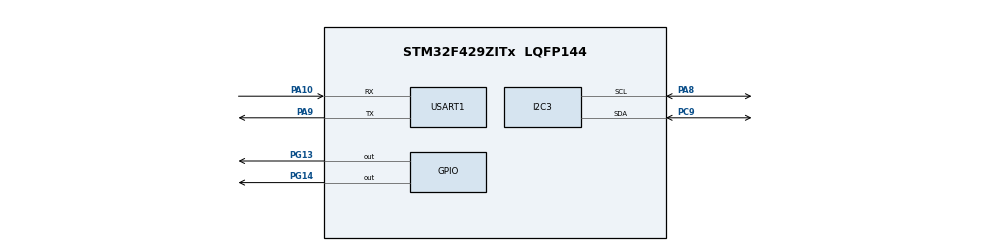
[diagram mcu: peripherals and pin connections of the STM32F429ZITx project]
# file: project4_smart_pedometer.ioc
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FREERTOS.Mutexes01=myMutex01,Dynamic,NULL,Available
FREERTOS.Queues01=myQueue01,16,uint16_t,0,Dynamic,NULL,NULL
FREERTOS.Tasks01=defaultTask,0,128,StartDefaultTask,Default,NULL,Dynamic,NULL,NULL
FREERTOS.configUSE_NEWLIB_REENTRANT=1
FREERTOS.configUSE_TIMERS=1
Mcu.Family=STM32F4
Mcu.Name=STM32F429ZITx
Mcu.Package=LQFP144
NVIC.PriorityGroup=NVIC_PRIORITYGROUP_4
NVIC.TIM1_UP_TIM10_IRQn=true\:15\:0\:false\:false\:true\:false\:false\:true\:true
NVIC.TimeBase=TIM1_UP_TIM10_IRQn
NVIC.TimeBaseIP=TIM1
NVIC.USART1_IRQn=true\:5\:0\:false\:false\:true\:true\:true\:true\:true
PA10.Mode=Asynchronous
PA10.Signal=USART1_RX
PA8.Mode=I2C
PA8.Signal=I2C3_SCL
PA9.Mode=Asynchronous
PA9.Signal=USART1_TX
PC9.Mode=I2C
PC9.Signal=I2C3_SDA
PG13.Signal=GPIO_Output
PG14.Signal=GPIO_Output
ProjectManager.HeapSize=0x200
ProjectManager.StackSize=0x400
ProjectManager.TargetToolchain=STM32CubeIDE
RCC.48MHZClocksFreq_Value=90000000
RCC.AHBFreq_Value=180000000
RCC.APB1CLKDivider=RCC_HCLK_DIV4
RCC.APB1Freq_Value=45000000
RCC.APB1TimFreq_Value=90000000
RCC.APB2CLKDivider=RCC_HCLK_DIV2
RCC.APB2Freq_Value=90000000
RCC.APB2TimFreq_Value=180000000
RCC.CortexFreq_Value=180000000
RCC.HCLKFreq_Value=180000000
RCC.HSE_VALUE=25000000
RCC.HSI_VALUE=16000000
RCC.LSE_VALUE=32768
RCC.PLLM=8
RCC.PLLN=180
RCC.SYSCLKFreq_VALUE=180000000
RCC.SYSCLKSource=RCC_SYSCLKSOURCE_PLLCLK
RCC.VCOOutputFreq_Value=360000000
USART1.VirtualMode=VM_ASYNC
VP_FREERTOS_VS_CMSIS_V1.Mode=CMSIS_V1
VP_SYS_VS_tim1.Mode=TIM1
board=custom

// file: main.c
/* USER CODE BEGIN Header */
/**
  ******************************************************************************
  * @file           : main.c
  * @brief          : Main program body
  ******************************************************************************
  * @attention
  *
  * Copyright (c) 2026 STMicroelectronics.
  * All rights reserved.
  *
  * This software is licensed under terms that can be found in the LICENSE file
  * in the root directory of this software component.
  * If no LICENSE file comes with this software, it is provided AS-IS.
  *
  ******************************************************************************
  */
/* USER CODE END Header */
#include "main.h"
#include "cmsis_os.h"

/* USER CODE BEGIN Includes */
#include <stdio.h>

/* USER CODE END Includes */

/* USER CODE BEGIN PTD */
#include <stdio.h>
#include <string.h>
#include <math.h>

void MPU6050_Init(void);
void MPU6050_Read(void);
#define MPU6050_ADDR (0x68 << 1)
uint8_t data[14];
uint16_t g_Ax, g_Ay, g_Az, g_Gx, g_Gy, g_Gz;
char uart_buf[100];

TaskHandle_t sensortaskHandle,pedometertaskhandle,displayhandle;
QueueHandle_t alertQueue;
/* USER CODE END PTD */

I2C_HandleTypeDef hi2c3;

UART_HandleTypeDef huart1;

osThreadId defaultTaskHandle;
osThreadId myTask02Handle;
osTimerId myTimer01Handle;
osMutexId myMutex01Handle;

void SystemClock_Config(void);
static void MX_GPIO_Init(void);
static void MX_I2C3_Init(void);
static void MX_USART1_UART_Init(void);
//void StartDefaultTask(void const * argument);
void StartTask02(void const * argument);
void Callback01(void const * argument);

/* USER CODE BEGIN 0 */
void MPU6050_Init(void)
{
  uint8_t check;
  uint8_t data;

  // Check WHO_AM_I
  HAL_I2C_Mem_Read(&hi2c3, MPU6050_ADDR, 0x75, 1, &check, 1, HAL_MAX_DELAY);

  // Wake up MPU6050
  data = 0;
  HAL_I2C_Mem_Write(&hi2c3, MPU6050_ADDR, 0x6B, 1, &data, 1, HAL_MAX_DELAY);

  // Set accel ±2g
  data = 0x00;
  HAL_I2C_Mem_Write(&hi2c3, MPU6050_ADDR, 0x1C, 1, &data, 1, HAL_MAX_DELAY);

  // Set gyro ±250 dps
  data = 0x00;
  HAL_I2C_Mem_Write(&hi2c3, MPU6050_ADDR, 0x1B, 1, &data, 1, HAL_MAX_DELAY);
}
void MPU6050_Read(void)
{
  HAL_I2C_Mem_Read(&hi2c3, MPU6050_ADDR, 0x3B, 1, data, 14, HAL_MAX_DELAY);

  g_Ax = (int16_t)(data[0] << 8 | data[1]);
  g_Ay = (int16_t)(data[2] << 8 | data[3]);
  g_Az = (int16_t)(data[4] << 8 | data[5]);

  g_Gx = (int16_t)(data[8] << 8 | data[9]);
  g_Gy = (int16_t)(data[10] << 8 | data[11]);
  g_Gz = (int16_t)(data[12] << 8 | data[13]);
}

void SensorTask(void*arg);
void Pedometertask(void*arg);
void Displaytask(void*arg);
/* USER CODE END 0 */

int main(void)
{

  /* MCU Configuration--------------------------------------------------------*/

  /* Reset of all peripherals, Initializes the Flash interface and the Systick. */
  HAL_Init();

  /* Configure the system clock */
  SystemClock_Config();

  /* Initialize all configured peripherals */
  MX_GPIO_Init();
  MX_I2C3_Init();
  MX_USART1_UART_Init();
  /* USER CODE BEGIN 2 */
  MPU6050_Init(); //imp

  // queue to send the data form pedometer to the alert task
  alertQueue = xQueueCreate(5,sizeof(int));

  TaskHandle_t sensortaskHandle,pedometertaskhandle,displayhandle;

  xTaskCreate(SensorTask,"Sensor",128, NULL, 1,&sensortaskHandle);
  xTaskCreate(Pedometertask,"Pedometer",128, NULL, 2,&pedometertaskhandle);
  xTaskCreate(Displaytask,"Display",256, NULL,1,&displayhandle);

  vTaskStartScheduler(); // oskernal start

  /* USER CODE END 2 */

  /* Create the mutex(es) */
  /* definition and creation of myMutex01 */
//  osMutexDef(myMutex01);
//  myMutex01Handle = osMutexCreate(osMutex(myMutex01));

  /* Create the timer(s) */
  /* definition and creation of myTimer01 */
//  osTimerDef(myTimer01, Callback01);
//  myTimer01Handle = osTimerCreate(osTimer(myTimer01), osTimerPeriodic, NULL);

  /* Create the thread(s) */
  /* definition and creation of defaultTask */
//  osThreadDef(defaultTask, StartDefaultTask, osPriorityNormal, 0, 128);
//  defaultTaskHandle = osThreadCreate(osThread(defaultTask), NULL);

  /* definition and creation of myTask02 */
//  osThreadDef(myTask02, StartTask02, osPriorityIdle, 0, 128);
//  myTask02Handle = osThreadCreate(osThread(myTask02), NULL);

  /* Start scheduler */
  //osKernelStart();

  /* We should never get here as control is now taken by the scheduler */

  /* Infinite loop */
  while (1)
  {

  }
}

void SystemClock_Config(void)
{
  RCC_OscInitTypeDef RCC_OscInitStruct = {0};
  RCC_ClkInitTypeDef RCC_ClkInitStruct = {0};

  /** Configure the main internal regulator output voltage
  */
  __HAL_RCC_PWR_CLK_ENABLE();
  __HAL_PWR_VOLTAGESCALING_CONFIG(PWR_REGULATOR_VOLTAGE_SCALE3);

  /** Initializes the RCC Oscillators according to the specified parameters
  * in the RCC_OscInitTypeDef structure.
  */
  RCC_OscInitStruct.OscillatorType = RCC_OSCILLATORTYPE_HSI;
  RCC_OscInitStruct.HSIState = RCC_HSI_ON;
  RCC_OscInitStruct.HSICalibrationValue = RCC_HSICALIBRATION_DEFAULT;
  RCC_OscInitStruct.PLL.PLLState = RCC_PLL_NONE;
  if (HAL_RCC_OscConfig(&RCC_OscInitStruct) != HAL_OK)
  {
    Error_Handler();
  }

  /** Initializes the CPU, AHB and APB buses clocks
  */
  RCC_ClkInitStruct.ClockType = RCC_CLOCKTYPE_HCLK|RCC_CLOCKTYPE_SYSCLK
                              |RCC_CLOCKTYPE_PCLK1|RCC_CLOCKTYPE_PCLK2;
  RCC_ClkInitStruct.SYSCLKSource = RCC_SYSCLKSOURCE_HSI;
  RCC_ClkInitStruct.AHBCLKDivider = RCC_SYSCLK_DIV1;
  RCC_ClkInitStruct.APB1CLKDivider = RCC_HCLK_DIV1;
  RCC_ClkInitStruct.APB2CLKDivider = RCC_HCLK_DIV1;

  if (HAL_RCC_ClockConfig(&RCC_ClkInitStruct, FLASH_LATENCY_0) != HAL_OK)
  {
    Error_Handler();
  }
}

static void MX_I2C3_Init(void)
{

  hi2c3.Instance = I2C3;
  hi2c3.Init.ClockSpeed = 100000;
  hi2c3.Init.DutyCycle = I2C_DUTYCYCLE_2;
  hi2c3.Init.OwnAddress1 = 0;
  hi2c3.Init.AddressingMode = I2C_ADDRESSINGMODE_7BIT;
  hi2c3.Init.DualAddressMode = I2C_DUALADDRESS_DISABLE;
  hi2c3.Init.OwnAddress2 = 0;
  hi2c3.Init.GeneralCallMode = I2C_GENERALCALL_DISABLE;
  hi2c3.Init.NoStretchMode = I2C_NOSTRETCH_DISABLE;
  if (HAL_I2C_Init(&hi2c3) != HAL_OK)
  {
    Error_Handler();
  }

  /** Configure Analogue filter
  */
  if (HAL_I2CEx_ConfigAnalogFilter(&hi2c3, I2C_ANALOGFILTER_ENABLE) != HAL_OK)
  {
    Error_Handler();
  }

  /** Configure Digital filter
  */
  if (HAL_I2CEx_ConfigDigitalFilter(&hi2c3, 0) != HAL_OK)
  {
    Error_Handler();
  }

}

static void MX_USART1_UART_Init(void)
{

  huart1.Instance = USART1;
  huart1.Init.BaudRate = 115200;
  huart1.Init.WordLength = UART_WORDLENGTH_8B;
  huart1.Init.StopBits = UART_STOPBITS_1;
  huart1.Init.Parity = UART_PARITY_NONE;
  huart1.Init.Mode = UART_MODE_TX_RX;
  huart1.Init.HwFlowCtl = UART_HWCONTROL_NONE;
  huart1.Init.OverSampling = UART_OVERSAMPLING_16;
  if (HAL_UART_Init(&huart1) != HAL_OK)
  {
    Error_Handler();
  }

}

static void MX_GPIO_Init(void)
{
  GPIO_InitTypeDef GPIO_InitStruct = {0};

  /* GPIO Ports Clock Enable */
  __HAL_RCC_GPIOC_CLK_ENABLE();
  __HAL_RCC_GPIOA_CLK_ENABLE();
  __HAL_RCC_GPIOG_CLK_ENABLE();

  /*Configure GPIO pin Output Level */
  HAL_GPIO_WritePin(GPIOG, GPIO_PIN_13|GPIO_PIN_14, GPIO_PIN_RESET);

  /*Configure GPIO pins : PG13 PG14 */
  GPIO_InitStruct.Pin = GPIO_PIN_13|GPIO_PIN_14;
  GPIO_InitStruct.Mode = GPIO_MODE_OUTPUT_PP;
  GPIO_InitStruct.Pull = GPIO_NOPULL;
  GPIO_InitStruct.Speed = GPIO_SPEED_FREQ_LOW;
  HAL_GPIO_Init(GPIOG, &GPIO_InitStruct);

}

/* USER CODE BEGIN 4 */

//PedometerTask
//      │
//      │  xQueueSend(alertQueue, &step_count)
//      ▼
//Queue
//      ▼
//DisplayTask
//      │
//      │ xQueueReceive()
//      ▼
//Print steps to UART

void SensorTask(void *arg)
{
	for(;;)
	{
		MPU6050_Read();  // read the sensor

//		sprintf(uart_buf, "Ax=%d Ay=%d Az=%d | Gx=%d Gy=%d Gz=%d\r\n", g_Ax, g_Ay, g_Az, g_Gx, g_Gy, g_Gz);
//
//		HAL_UART_Transmit(&huart1, (uint8_t*)uart_buf, strlen(uart_buf), portMAX_DELAY);

		HAL_GPIO_TogglePin(GPIOG, GPIO_PIN_13);  // sending the sensor task

		vTaskDelay(pdMS_TO_TICKS(20));
	}
}
void Pedometertask(void*arg)
{
	int step_count = 0;
	float prev_magnitude = 0.0f;
	float magnitude;
	while(1)
	{
		// TODO: Calculate acceleration magnitude
		magnitude = sqrt(g_Ax*g_Ax +g_Ay*g_Ay +g_Az*g_Az);

		// TODO: Calculate swing speed from gyroscope
		float gyro_dps = g_Gy / 131.0;

		// TODO: Implement the step detection logic (Threshold + Edge + Swing)
		if(magnitude > 18000 && prev_magnitude < 18000 &&fabs(gyro_dps) > 15)
		{
			step_count++;

			// TODO: If step detected, send to queue and apply cooldown delay

			xQueueSend(alertQueue, &step_count, 0);

			vTaskDelay(pdMS_TO_TICKS(250));
		}

		// TODO: Update prev_magnitude
		prev_magnitude = magnitude;
		vTaskDelay(pdMS_TO_TICKS(20));
	}
}

void Displaytask(void*arg)
{
	int steps;
	uint16_t uart_buf[50];
	for(;;)
	{
			xQueueReceive(alertQueue,&steps,portMAX_DELAY);

			sprintf(uart_buf,"Steps: %d\r\n",steps);

			HAL_UART_Transmit(&huart1,(uint8_t*)uart_buf,strlen(uart_buf),HAL_MAX_DELAY);
	}
}
/* USER CODE END 4 */

void StartDefaultTask(void const * argument)
{
  /* USER CODE BEGIN 5 */
//  /* Infinite loop */
//  for(;;)
//  {
//    osDelay(1);
//  }
  /* USER CODE END 5 */
}

void StartTask02(void const * argument)
{
  /* USER CODE BEGIN StartTask02 */
//  /* Infinite loop */
//  for(;;)
//  {
//    osDelay(1);
//  }
  /* USER CODE END StartTask02 */
}

/* Callback01 function */
void Callback01(void const * argument)
{
  /* USER CODE BEGIN Callback01 */
//
  /* USER CODE END Callback01 */
}

void HAL_TIM_PeriodElapsedCallback(TIM_HandleTypeDef *htim)
{
  /* USER CODE BEGIN Callback 0 */
//
  /* USER CODE END Callback 0 */
  if (htim->Instance == TIM1)
  {
    HAL_IncTick();
  }
  /* USER CODE BEGIN Callback 1 */
//
  /* USER CODE END Callback 1 */
}

void Error_Handler(void)
{
  __disable_irq();
  while (1)
  {
  }
}
